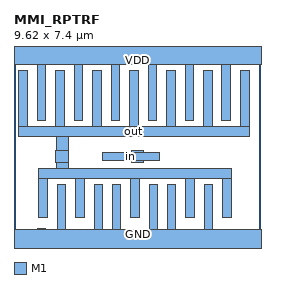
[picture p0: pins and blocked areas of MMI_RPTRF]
MACRO MMI_RPTRF
	CLASS CORE ;
	FOREIGN MMI_RPTRF 0 0 ;
	SIZE 9.62 BY 7.4 ;
	SYMMETRY X Y ;
	SITE CORE1 ;
	PIN out
		DIRECTION output ;
		USE SIGNAL ;
		PORT
			LAYER M1 ;
			RECT 0.18 4.515 0.52 6.665 ;
			LAYER M1 ;
			RECT 1.62 4.515 1.96 6.665 ;
			LAYER M1 ;
			RECT 3.06 4.515 3.4 6.665 ;
			LAYER M1 ;
			RECT 4.5 4.515 4.84 6.665 ;
			LAYER M1 ;
			RECT 5.94 4.515 6.28 6.665 ;
			LAYER M1 ;
			RECT 7.38 4.515 7.72 6.665 ;
			LAYER M1 ;
			RECT 8.82 4.515 9.16 6.665 ;
			LAYER M1 ;
			RECT 0.18 4.115 9.16 4.515 ;
			LAYER M1 ;
			RECT 1.66 3.555 2.115 4.115 ;
			LAYER M1 ;
			RECT 1.625 3.105 2.115 3.555 ;
			LAYER M1 ;
			RECT 1.66 2.865 2.115 3.105 ;
			LAYER M1 ;
			RECT 0.955 2.465 8.46 2.865 ;
			LAYER M1 ;
			RECT 0.955 0.935 1.295 2.465 ;
			LAYER M1 ;
			RECT 2.4 0.935 2.74 2.465 ;
			LAYER M1 ;
			RECT 4.54 0.935 4.88 2.465 ;
			LAYER M1 ;
			RECT 6.68 0.935 7.02 2.465 ;
			LAYER M1 ;
			RECT 8.12 0.935 8.46 2.465 ;
		END
		AntennaDiffArea 13.7325 ;
	END out
	PIN GND
		DIRECTION inout ;
		USE GROUND ;
		PORT
			LAYER M1 ;
			RECT 0.9 0.5 1.24 0.525 ;
			LAYER M1 ;
			RECT 1.68 0.5 2.02 2.235 ;
			LAYER M1 ;
			RECT 3.12 0.5 3.46 2.235 ;
			LAYER M1 ;
			RECT 3.82 0.5 4.16 2.235 ;
			LAYER M1 ;
			RECT 5.26 0.5 5.6 2.235 ;
			LAYER M1 ;
			RECT 5.96 0.5 6.3 2.235 ;
			LAYER M1 ;
			RECT 7.4 0.5 7.74 2.235 ;
			LAYER M1 ;
			RECT 0 -0.5 9.62 0.5 ;
		END
	END GND
	PIN VDD
		DIRECTION inout ;
		USE POWER ;
		PORT
			LAYER M1 ;
			RECT 0 6.9 9.62 7.9 ;
			LAYER M1 ;
			RECT 0.9 4.75 1.24 6.9 ;
			LAYER M1 ;
			RECT 2.34 4.75 2.68 6.9 ;
			LAYER M1 ;
			RECT 3.78 4.75 4.12 6.9 ;
			LAYER M1 ;
			RECT 5.22 4.75 5.56 6.9 ;
			LAYER M1 ;
			RECT 6.66 4.75 7 6.9 ;
			LAYER M1 ;
			RECT 8.1 4.75 8.44 6.9 ;
		END
	END VDD
	PIN in
		DIRECTION input ;
		USE SIGNAL ;
		PORT
			LAYER M1 ;
			RECT 4.585 3.5 5.035 3.555 ;
			LAYER M1 ;
			RECT 3.44 3.16 5.66 3.5 ;
			LAYER M1 ;
			RECT 4.585 3.105 5.035 3.16 ;
			LAYER M1 ;
			RECT 4.586 3.104 5.034 3.105 ;
		END
		AntennaGateArea 7.9524 ;
	END in
	OBS
	END
END MMI_RPTRF
